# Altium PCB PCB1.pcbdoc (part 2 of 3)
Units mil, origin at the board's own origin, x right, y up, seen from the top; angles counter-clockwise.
Board outline 1393.7 x 1462.72 mil, 2 copper layers (Top Layer, Bottom Layer), stack 62.206 mil thick; 10 components, 35 nets, 86 pads, 11 vias.

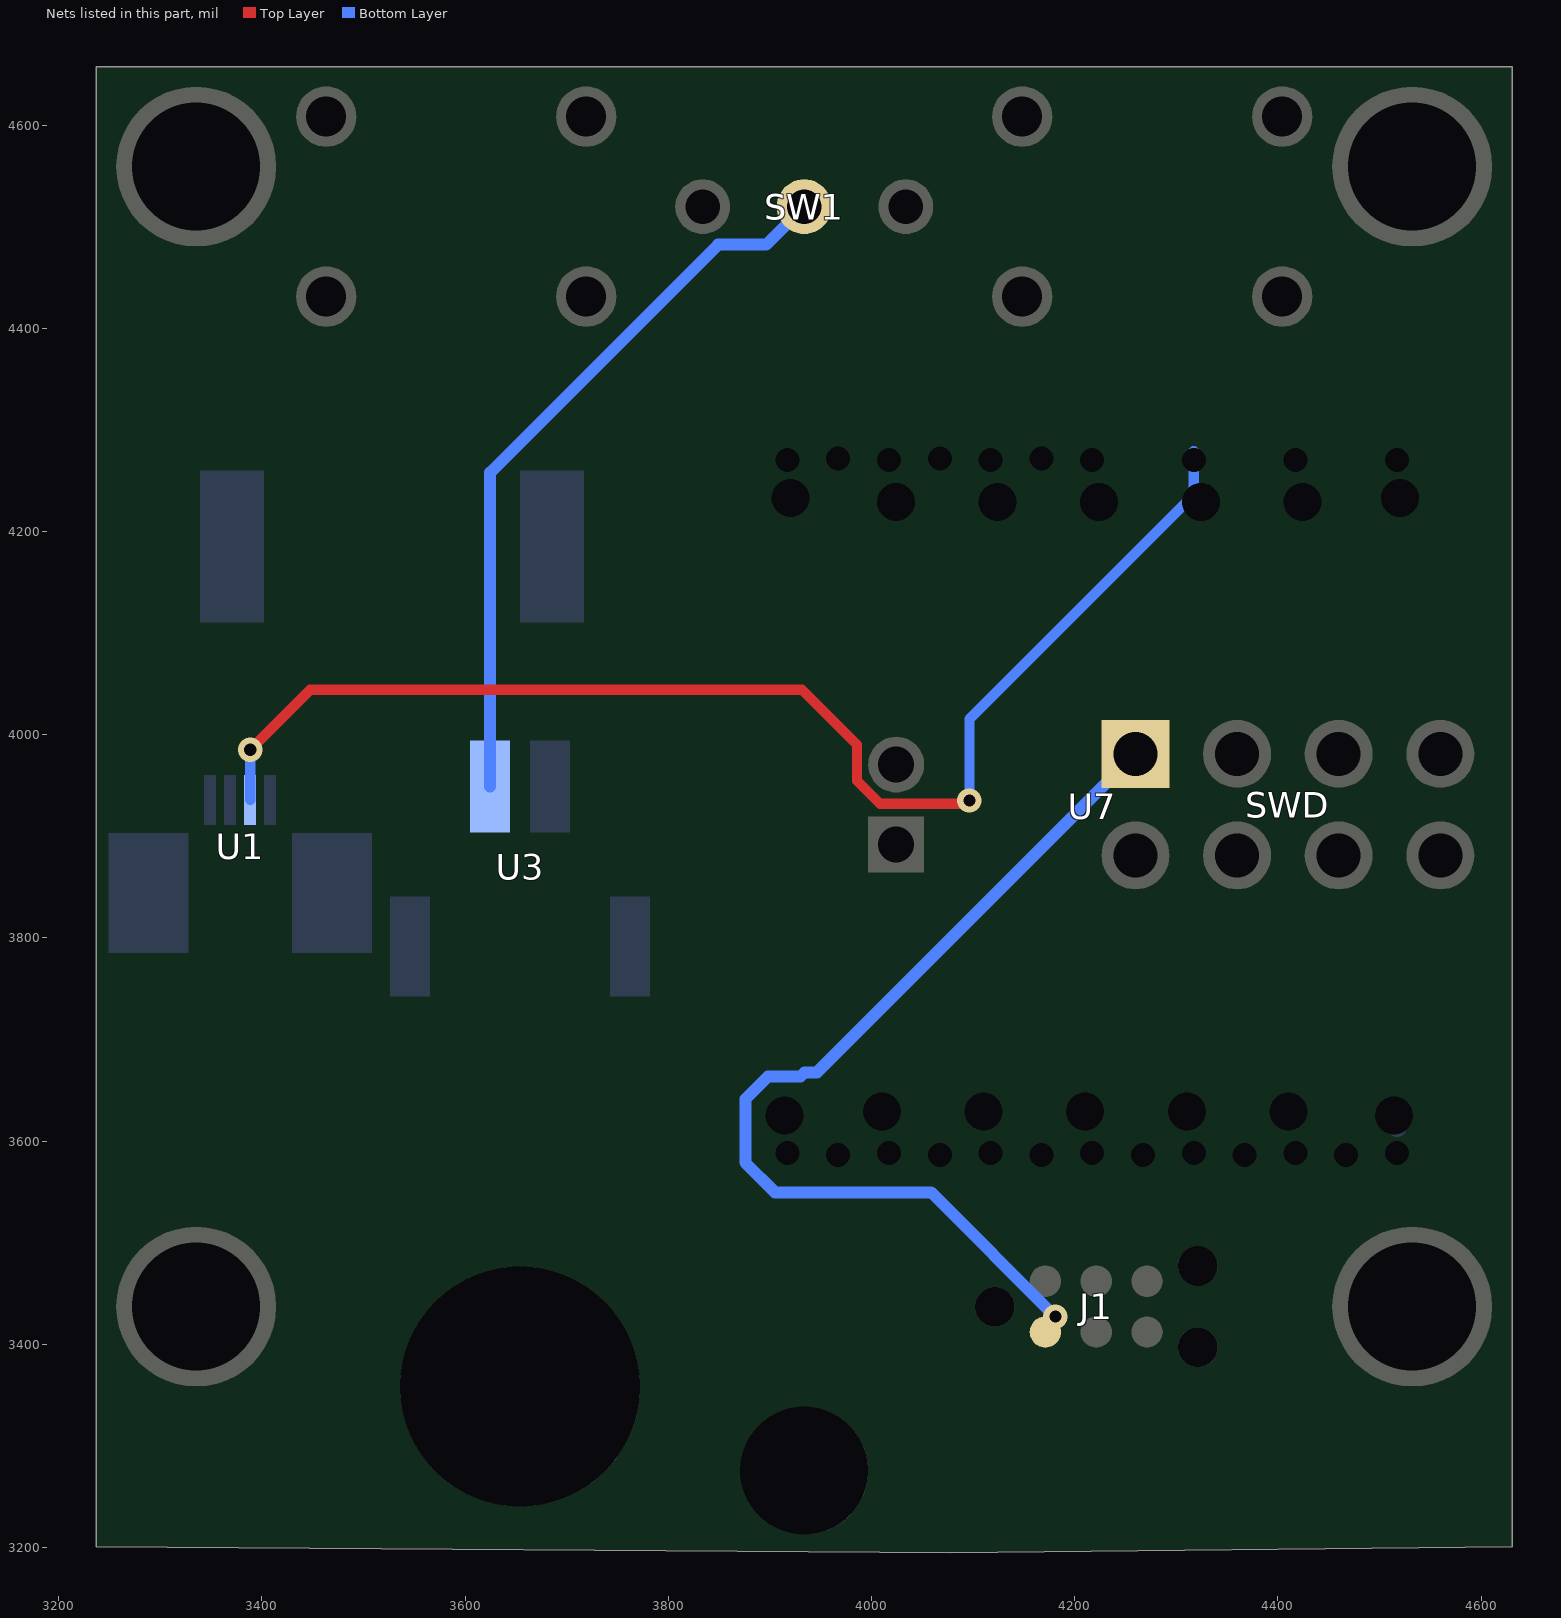
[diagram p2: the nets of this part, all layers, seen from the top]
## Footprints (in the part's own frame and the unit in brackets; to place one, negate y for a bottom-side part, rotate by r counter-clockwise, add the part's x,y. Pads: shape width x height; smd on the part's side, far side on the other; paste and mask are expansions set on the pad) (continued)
Claude_buddy_Seeed_Studio_XIAO_Series:XIAO-Add-On-PRO [mm]
  round 0.673 hole 0.95: 1(7.545,7.72) 2(4.905,7.62) 3(2.365,7.62) 4(-0.175,7.62) 5(-2.715,7.62) 6(-5.255,7.62) 7(-7.695,7.72) 8(-7.545,-7.72) 9(-4.905,-7.62) 10(-2.365,-7.62) 11(0.175,-7.62) 12(2.715,-7.62) 13(5.255,-7.62) 14(7.695,-7.72)
  round 0.475 smd: 1(7.62,8.028)
  round 0.452 hole 0.6: 1(7.62,8.663) 2(5.08,8.663) 3(2.54,8.663) 4(0,8.663) 5(-2.54,8.663) 6(-5.08,8.663) 7(-7.62,8.663) 8(-7.62,-8.663) 9(-5.08,-8.663) 10(-2.54,-8.663) 11(0,-8.663) 12(2.54,-8.663) 13(5.08,-8.663) 14(7.62,-8.663)
  round 0.451 hole 0.6: 15(6.351,8.708) 16(3.811,8.708) 17(1.271,8.708) 18(-1.269,8.708) 19(-3.809,8.708) 20(-6.349,8.708) 21(-6.351,-8.708) 22(-3.811,-8.708) 23(-1.271,-8.708)
  Top Layer region: 7.173,8.941 7.193,9.032 7.232,9.117 7.287,9.193 7.357,9.255 7.438,9.302 7.527,9.33 7.62,9.34 7.713,9.33 7.802,9.302 7.883,9.255 7.953,9.193 8.008,9.117 8.047,9.032 8.067,8.941 8.072,8.941 8.072,8.077 7.168,8.077 7.168,8.941 7.173,8.941
  Top Layer region: 7.145,8.881 7.154,8.891 8.086,8.891 8.095,8.881 8.095,7.166 7.145,7.166
  Top Layer region: 7.545,7.045 7.439,7.053 7.336,7.078 7.239,7.119 7.148,7.174 7.068,7.243 6.999,7.323 6.944,7.414 6.903,7.511 6.878,7.614 6.87,7.72 6.878,7.826 6.903,7.929 6.944,8.026 6.999,8.117 7.068,8.197 7.148,8.266 7.239,8.321 7.336,8.362 7.439,8.387 7.545,8.395 7.651,8.387 7.754,8.362 7.851,8.321 7.942,8.266 8.022,8.197 8.091,8.117 8.146,8.026 8.187,7.929 8.212,7.826 8.22,7.72 8.212,7.614 8.187,7.511 8.146,7.414 8.091,7.323 8.022,7.243 7.942,7.174 7.851,7.119 7.754,7.078 7.651,7.053 7.545,7.045
  Top Layer region: 4.633,8.941 4.653,9.032 4.692,9.117 4.747,9.193 4.817,9.255 4.898,9.302 4.987,9.33 5.08,9.34 5.173,9.33 5.262,9.302 5.343,9.255 5.413,9.193 5.468,9.117 5.507,9.032 5.527,8.941 5.532,8.941 5.532,8.077 4.628,8.077 4.628,8.941 4.633,8.941
  Top Layer region: 4.905,6.945 4.799,6.953 4.696,6.978 4.599,7.019 4.508,7.074 4.428,7.143 4.359,7.223 4.304,7.314 4.263,7.411 4.238,7.514 4.23,7.62 4.238,7.726 4.263,7.829 4.304,7.926 4.359,8.017 4.428,8.097 4.508,8.166 4.599,8.221 4.696,8.262 4.799,8.287 4.905,8.295 5.011,8.287 5.114,8.262 5.211,8.221 5.302,8.166 5.382,8.097 5.451,8.017 5.506,7.926 5.547,7.829 5.572,7.726 5.58,7.62 5.572,7.514 5.547,7.411 5.506,7.314 5.451,7.223 5.382,7.143 5.302,7.074 5.211,7.019 5.114,6.978 5.011,6.953 4.905,6.945
  Top Layer region: 2.093,8.941 2.113,9.032 2.152,9.117 2.207,9.193 2.277,9.255 2.358,9.302 2.447,9.33 2.54,9.34 2.633,9.33 2.722,9.302 2.803,9.255 2.873,9.193 2.928,9.117 2.967,9.032 2.987,8.941 2.992,8.941 2.992,8.077 2.088,8.077 2.088,8.941 2.093,8.941
  Top Layer region: 2.365,6.945 2.259,6.953 2.156,6.978 2.059,7.019 1.968,7.074 1.888,7.143 1.819,7.223 1.764,7.314 1.723,7.411 1.698,7.514 1.69,7.62 1.698,7.726 1.723,7.829 1.764,7.926 1.819,8.017 1.888,8.097 1.968,8.166 2.059,8.221 2.156,8.262 2.259,8.287 2.365,8.295 2.471,8.287 2.574,8.262 2.671,8.221 2.762,8.166 2.842,8.097 2.911,8.017 2.966,7.926 3.007,7.829 3.032,7.726 3.04,7.62 3.032,7.514 3.007,7.411 2.966,7.314 2.911,7.223 2.842,7.143 2.762,7.074 2.671,7.019 2.574,6.978 2.471,6.953 2.365,6.945
  Top Layer region: -0.447,8.941 -0.427,9.032 -0.388,9.117 -0.333,9.193 -0.263,9.255 -0.182,9.302 -0.093,9.33 0,9.34 0.093,9.33 0.182,9.302 0.263,9.255 0.333,9.193 0.388,9.117 0.427,9.032 0.447,8.941 0.452,8.941 0.452,8.077 -0.452,8.077 -0.452,8.941 -0.447,8.941
  Top Layer region: -0.175,6.945 -0.281,6.953 -0.384,6.978 -0.481,7.019 -0.572,7.074 -0.652,7.143 -0.721,7.223 -0.776,7.314 -0.817,7.411 -0.842,7.514 -0.85,7.62 -0.842,7.726 -0.817,7.829 -0.776,7.926 -0.721,8.017 -0.652,8.097 -0.572,8.166 -0.481,8.221 -0.384,8.262 -0.281,8.287 -0.175,8.295 -0.069,8.287 0.034,8.262 0.131,8.221 0.222,8.166 0.302,8.097 0.371,8.017 0.426,7.926 0.467,7.829 0.492,7.726 0.5,7.62 0.492,7.514 0.467,7.411 0.426,7.314 0.371,7.223 0.302,7.143 0.222,7.074 0.131,7.019 0.034,6.978 -0.069,6.953 -0.175,6.945
  Top Layer region: -2.987,8.941 -2.967,9.032 -2.928,9.117 -2.873,9.193 -2.803,9.255 -2.722,9.302 -2.633,9.33 -2.54,9.34 -2.447,9.33 -2.358,9.302 -2.277,9.255 -2.207,9.193 -2.152,9.117 -2.113,9.032 -2.093,8.941 -2.088,8.941 -2.088,8.077 -2.992,8.077 -2.992,8.941 -2.987,8.941
  Top Layer region: -2.715,6.945 -2.821,6.953 -2.924,6.978 -3.021,7.019 -3.112,7.074 -3.192,7.143 -3.261,7.223 -3.316,7.314 -3.357,7.411 -3.382,7.514 -3.39,7.62 -3.382,7.726 -3.357,7.829 -3.316,7.926 -3.261,8.017 -3.192,8.097 -3.112,8.166 -3.021,8.221 -2.924,8.262 -2.821,8.287 -2.715,8.295 -2.609,8.287 -2.506,8.262 -2.409,8.221 -2.318,8.166 -2.238,8.097 -2.169,8.017 -2.114,7.926 -2.073,7.829 -2.048,7.726 -2.04,7.62 -2.048,7.514 -2.073,7.411 -2.114,7.314 -2.169,7.223 -2.238,7.143 -2.318,7.074 -2.409,7.019 -2.506,6.978 -2.609,6.953 -2.715,6.945
  Top Layer region: -5.527,8.941 -5.507,9.032 -5.468,9.117 -5.413,9.193 -5.343,9.255 -5.262,9.302 -5.173,9.33 -5.08,9.34 -4.987,9.33 -4.898,9.302 -4.817,9.255 -4.747,9.193 -4.692,9.117 -4.653,9.032 -4.633,8.941 -4.628,8.941 -4.628,8.077 -5.532,8.077 -5.532,8.941 -5.527,8.941
  Top Layer region: -5.255,6.945 -5.361,6.953 -5.464,6.978 -5.561,7.019 -5.652,7.074 -5.732,7.143 -5.801,7.223 -5.856,7.314 -5.897,7.411 -5.922,7.514 -5.93,7.62 -5.922,7.726 -5.897,7.829 -5.856,7.926 -5.801,8.017 -5.732,8.097 -5.652,8.166 -5.561,8.221 -5.464,8.262 -5.361,8.287 -5.255,8.295 -5.149,8.287 -5.046,8.262 -4.949,8.221 -4.858,8.166 -4.778,8.097 -4.709,8.017 -4.654,7.926 -4.613,7.829 -4.588,7.726 -4.58,7.62 -4.588,7.514 -4.613,7.411 -4.654,7.314 -4.709,7.223 -4.778,7.143 -4.858,7.074 -4.949,7.019 -5.046,6.978 -5.149,6.953 -5.255,6.945
  Top Layer region: -8.067,8.941 -8.047,9.032 -8.008,9.117 -7.953,9.193 -7.883,9.255 -7.802,9.302 -7.713,9.33 -7.62,9.34 -7.527,9.33 -7.438,9.302 -7.357,9.255 -7.287,9.193 -7.232,9.117 -7.193,9.032 -7.173,8.941 -7.168,8.941 -7.168,8.077 -8.072,8.077 -8.072,8.941 -8.067,8.941
  Top Layer region: -7.695,7.045 -7.801,7.053 -7.904,7.078 -8.001,7.119 -8.092,7.174 -8.172,7.243 -8.241,7.323 -8.296,7.414 -8.337,7.511 -8.362,7.614 -8.37,7.72 -8.362,7.826 -8.337,7.929 -8.296,8.026 -8.241,8.117 -8.172,8.197 -8.092,8.266 -8.001,8.321 -7.904,8.362 -7.801,8.387 -7.695,8.395 -7.589,8.387 -7.486,8.362 -7.389,8.321 -7.298,8.266 -7.218,8.197 -7.149,8.117 -7.094,8.026 -7.053,7.929 -7.028,7.826 -7.02,7.72 -7.028,7.614 -7.053,7.511 -7.094,7.414 -7.149,7.323 -7.218,7.243 -7.298,7.174 -7.389,7.119 -7.486,7.078 -7.589,7.053 -7.695,7.045
  Top Layer region: -7.545,-8.395 -7.651,-8.387 -7.754,-8.362 -7.851,-8.321 -7.942,-8.266 -8.022,-8.197 -8.091,-8.117 -8.146,-8.026 -8.187,-7.929 -8.212,-7.826 -8.22,-7.72 -8.212,-7.614 -8.187,-7.511 -8.146,-7.414 -8.091,-7.323 -8.022,-7.243 -7.942,-7.174 -7.851,-7.119 -7.754,-7.078 -7.651,-7.053 -7.545,-7.045 -7.439,-7.053 -7.336,-7.078 -7.239,-7.119 -7.148,-7.174 -7.068,-7.243 -6.999,-7.323 -6.944,-7.414 -6.903,-7.511 -6.878,-7.614 -6.87,-7.72 -6.878,-7.826 -6.903,-7.929 -6.944,-8.026 -6.999,-8.117 -7.068,-8.197 -7.148,-8.266 -7.239,-8.321 -7.336,-8.362 -7.439,-8.387 -7.545,-8.395
  Top Layer region: -7.173,-8.941 -7.193,-9.032 -7.232,-9.117 -7.287,-9.193 -7.357,-9.255 -7.438,-9.302 -7.527,-9.33 -7.62,-9.34 -7.713,-9.33 -7.802,-9.302 -7.883,-9.255 -7.953,-9.193 -8.008,-9.117 -8.047,-9.032 -8.067,-8.941 -8.072,-8.941 -8.072,-8.077 -7.168,-8.077 -7.168,-8.941 -7.173,-8.941
  Top Layer region: -4.905,-8.295 -5.011,-8.287 -5.114,-8.262 -5.211,-8.221 -5.302,-8.166 -5.382,-8.097 -5.451,-8.017 -5.506,-7.926 -5.547,-7.829 -5.572,-7.726 -5.58,-7.62 -5.572,-7.514 -5.547,-7.411 -5.506,-7.314 -5.451,-7.223 -5.382,-7.143 -5.302,-7.074 -5.211,-7.019 -5.114,-6.978 -5.011,-6.953 -4.905,-6.945 -4.799,-6.953 -4.696,-6.978 -4.599,-7.019 -4.508,-7.074 -4.428,-7.143 -4.359,-7.223 -4.304,-7.314 -4.263,-7.411 -4.238,-7.514 -4.23,-7.62 -4.238,-7.726 -4.263,-7.829 -4.304,-7.926 -4.359,-8.017 -4.428,-8.097 -4.508,-8.166 -4.599,-8.221 -4.696,-8.262 -4.799,-8.287 -4.905,-8.295
  Top Layer region: -4.633,-8.941 -4.653,-9.032 -4.692,-9.117 -4.747,-9.193 -4.817,-9.255 -4.898,-9.302 -4.987,-9.33 -5.08,-9.34 -5.173,-9.33 -5.262,-9.302 -5.343,-9.255 -5.413,-9.193 -5.468,-9.117 -5.507,-9.032 -5.527,-8.941 -5.532,-8.941 -5.532,-8.077 -4.628,-8.077 -4.628,-8.941 -4.633,-8.941
  Top Layer region: -2.365,-8.295 -2.471,-8.287 -2.574,-8.262 -2.671,-8.221 -2.762,-8.166 -2.842,-8.097 -2.911,-8.017 -2.966,-7.926 -3.007,-7.829 -3.032,-7.726 -3.04,-7.62 -3.032,-7.514 -3.007,-7.411 -2.966,-7.314 -2.911,-7.223 -2.842,-7.143 -2.762,-7.074 -2.671,-7.019 -2.574,-6.978 -2.471,-6.953 -2.365,-6.945 -2.259,-6.953 -2.156,-6.978 -2.059,-7.019 -1.968,-7.074 -1.888,-7.143 -1.819,-7.223 -1.764,-7.314 -1.723,-7.411 -1.698,-7.514 -1.69,-7.62 -1.698,-7.726 -1.723,-7.829 -1.764,-7.926 -1.819,-8.017 -1.888,-8.097 -1.968,-8.166 -2.059,-8.221 -2.156,-8.262 -2.259,-8.287 -2.365,-8.295
  Top Layer region: -2.093,-8.941 -2.113,-9.032 -2.152,-9.117 -2.207,-9.193 -2.277,-9.255 -2.358,-9.302 -2.447,-9.33 -2.54,-9.34 -2.633,-9.33 -2.722,-9.302 -2.803,-9.255 -2.873,-9.193 -2.928,-9.117 -2.967,-9.032 -2.987,-8.941 -2.992,-8.941 -2.992,-8.077 -2.088,-8.077 -2.088,-8.941 -2.093,-8.941
  Top Layer region: 0.175,-8.295 0.069,-8.287 -0.034,-8.262 -0.131,-8.221 -0.222,-8.166 -0.302,-8.097 -0.371,-8.017 -0.426,-7.926 -0.467,-7.829 -0.492,-7.726 -0.5,-7.62 -0.492,-7.514 -0.467,-7.411 -0.426,-7.314 -0.371,-7.223 -0.302,-7.143 -0.222,-7.074 -0.131,-7.019 -0.034,-6.978 0.069,-6.953 0.175,-6.945 0.281,-6.953 0.384,-6.978 0.481,-7.019 0.572,-7.074 0.652,-7.143 0.721,-7.223 0.776,-7.314 0.817,-7.411 0.842,-7.514 0.85,-7.62 0.842,-7.726 0.817,-7.829 0.776,-7.926 0.721,-8.017 0.652,-8.097 0.572,-8.166 0.481,-8.221 0.384,-8.262 0.281,-8.287 0.175,-8.295
  Top Layer region: 0.447,-8.941 0.427,-9.032 0.388,-9.117 0.333,-9.193 0.263,-9.255 0.182,-9.302 0.093,-9.33 0,-9.34 -0.093,-9.33 -0.182,-9.302 -0.263,-9.255 -0.333,-9.193 -0.388,-9.117 -0.427,-9.032 -0.447,-8.941 -0.452,-8.941 -0.452,-8.077 0.452,-8.077 0.452,-8.941 0.447,-8.941
  Top Layer region: 2.715,-8.295 2.609,-8.287 2.506,-8.262 2.409,-8.221 2.318,-8.166 2.238,-8.097 2.169,-8.017 2.114,-7.926 2.073,-7.829 2.048,-7.726 2.04,-7.62 2.048,-7.514 2.073,-7.411 2.114,-7.314 2.169,-7.223 2.238,-7.143 2.318,-7.074 2.409,-7.019 2.506,-6.978 2.609,-6.953 2.715,-6.945 2.821,-6.953 2.924,-6.978 3.021,-7.019 3.112,-7.074 3.192,-7.143 3.261,-7.223 3.316,-7.314 3.357,-7.411 3.382,-7.514 3.39,-7.62 3.382,-7.726 3.357,-7.829 3.316,-7.926 3.261,-8.017 3.192,-8.097 3.112,-8.166 3.021,-8.221 2.924,-8.262 2.821,-8.287 2.715,-8.295
  Top Layer region: 2.987,-8.941 2.967,-9.032 2.928,-9.117 2.873,-9.193 2.803,-9.255 2.722,-9.302 2.633,-9.33 2.54,-9.34 2.447,-9.33 2.358,-9.302 2.277,-9.255 2.207,-9.193 2.152,-9.117 2.113,-9.032 2.093,-8.941 2.088,-8.941 2.088,-8.077 2.992,-8.077 2.992,-8.941 2.987,-8.941
  Top Layer region: 5.255,-8.295 5.149,-8.287 5.046,-8.262 4.949,-8.221 4.858,-8.166 4.778,-8.097 4.709,-8.017 4.654,-7.926 4.613,-7.829 4.588,-7.726 4.58,-7.62 4.588,-7.514 4.613,-7.411 4.654,-7.314 4.709,-7.223 4.778,-7.143 4.858,-7.074 4.949,-7.019 5.046,-6.978 5.149,-6.953 5.255,-6.945 5.361,-6.953 5.464,-6.978 5.561,-7.019 5.652,-7.074 5.732,-7.143 5.801,-7.223 5.856,-7.314 5.897,-7.411 5.922,-7.514 5.93,-7.62 5.922,-7.726 5.897,-7.829 5.856,-7.926 5.801,-8.017 5.732,-8.097 5.652,-8.166 5.561,-8.221 5.464,-8.262 5.361,-8.287 5.255,-8.295
  Top Layer region: 5.527,-8.941 5.507,-9.032 5.468,-9.117 5.413,-9.193 5.343,-9.255 5.262,-9.302 5.173,-9.33 5.08,-9.34 4.987,-9.33 4.898,-9.302 4.817,-9.255 4.747,-9.193 4.692,-9.117 4.653,-9.032 4.633,-8.941 4.628,-8.941 4.628,-8.077 5.532,-8.077 5.532,-8.941 5.527,-8.941
  Top Layer region: 7.695,-8.395 7.589,-8.387 7.486,-8.362 7.389,-8.321 7.298,-8.266 7.218,-8.197 7.149,-8.117 7.094,-8.026 7.053,-7.929 7.028,-7.826 7.02,-7.72 7.028,-7.614 7.053,-7.511 7.094,-7.414 7.149,-7.323 7.218,-7.243 7.298,-7.174 7.389,-7.119 7.486,-7.078 7.589,-7.053 7.695,-7.045 7.801,-7.053 7.904,-7.078 8.001,-7.119 8.092,-7.174 8.172,-7.243 8.241,-7.323 8.296,-7.414 8.337,-7.511 8.362,-7.614 8.37,-7.72 8.362,-7.826 8.337,-7.929 8.296,-8.026 8.241,-8.117 8.172,-8.197 8.092,-8.266 8.001,-8.321 7.904,-8.362 7.801,-8.387 7.695,-8.395
  Top Layer region: 8.067,-8.941 8.047,-9.032 8.008,-9.117 7.953,-9.193 7.883,-9.255 7.802,-9.302 7.713,-9.33 7.62,-9.34 7.527,-9.33 7.438,-9.302 7.357,-9.255 7.287,-9.193 7.232,-9.117 7.193,-9.032 7.173,-8.941 7.168,-8.941 7.168,-8.077 8.072,-8.077 8.072,-8.941 8.067,-8.941
  Top Layer region: 6.35,9.34 6.443,9.33 6.532,9.302 6.613,9.255 6.683,9.193 6.738,9.117 6.777,9.032 6.797,8.941 6.802,8.941 6.802,8.505 6.781,8.375 6.72,8.255 6.621,8.156 6.378,8.077 6.326,8.077 6.196,8.098 6.076,8.159 5.977,8.258 5.898,8.501 5.898,8.941 5.903,8.941 5.923,9.032 5.962,9.117 6.017,9.193 6.087,9.255 6.168,9.302 6.257,9.33 6.35,9.34
  Top Layer region: 3.81,9.34 3.903,9.33 3.992,9.302 4.073,9.255 4.143,9.193 4.198,9.117 4.237,9.032 4.257,8.941 4.262,8.941 4.262,8.505 4.241,8.375 4.18,8.255 4.081,8.156 3.838,8.077 3.786,8.077 3.656,8.098 3.536,8.159 3.437,8.258 3.358,8.501 3.358,8.941 3.363,8.941 3.383,9.032 3.422,9.117 3.477,9.193 3.547,9.255 3.628,9.302 3.717,9.33 3.81,9.34
  Top Layer region: 1.27,9.34 1.363,9.33 1.452,9.302 1.533,9.255 1.603,9.193 1.658,9.117 1.697,9.032 1.717,8.941 1.722,8.941 1.722,8.505 1.701,8.375 1.64,8.255 1.541,8.156 1.298,8.077 1.246,8.077 1.116,8.098 0.996,8.159 0.897,8.258 0.818,8.501 0.818,8.941 0.823,8.941 0.843,9.032 0.882,9.117 0.937,9.193 1.007,9.255 1.088,9.302 1.177,9.33 1.27,9.34
  Top Layer region: -1.27,9.34 -1.177,9.33 -1.088,9.302 -1.007,9.255 -0.937,9.193 -0.882,9.117 -0.843,9.032 -0.823,8.941 -0.818,8.941 -0.818,8.505 -0.839,8.375 -0.9,8.255 -0.999,8.156 -1.242,8.077 -1.294,8.077 -1.424,8.098 -1.544,8.159 -1.643,8.258 -1.722,8.501 -1.722,8.941 -1.717,8.941 -1.697,9.032 -1.658,9.117 -1.603,9.193 -1.533,9.255 -1.452,9.302 -1.363,9.33 -1.27,9.34
  Top Layer region: -3.81,9.34 -3.717,9.33 -3.628,9.302 -3.547,9.255 -3.477,9.193 -3.422,9.117 -3.383,9.032 -3.363,8.941 -3.358,8.941 -3.358,8.505 -3.379,8.375 -3.44,8.255 -3.539,8.156 -3.782,8.077 -3.834,8.077 -3.964,8.098 -4.084,8.159 -4.183,8.258 -4.262,8.501 -4.262,8.941 -4.257,8.941 -4.237,9.032 -4.198,9.117 -4.143,9.193 -4.073,9.255 -3.992,9.302 -3.903,9.33 -3.81,9.34
  Top Layer region: -6.35,9.34 -6.257,9.33 -6.168,9.302 -6.087,9.255 -6.017,9.193 -5.962,9.117 -5.923,9.032 -5.903,8.941 -5.898,8.941 -5.898,8.505 -5.919,8.375 -5.98,8.255 -6.079,8.156 -6.322,8.077 -6.374,8.077 -6.504,8.098 -6.624,8.159 -6.723,8.258 -6.802,8.501 -6.802,8.941 -6.797,8.941 -6.777,9.032 -6.738,9.117 -6.683,9.193 -6.613,9.255 -6.532,9.302 -6.443,9.33 -6.35,9.34
  Top Layer region: -6.35,-9.34 -6.443,-9.33 -6.532,-9.302 -6.613,-9.255 -6.683,-9.193 -6.738,-9.117 -6.777,-9.032 -6.797,-8.941 -6.802,-8.941 -6.802,-8.505 -6.781,-8.375 -6.72,-8.255 -6.621,-8.156 -6.378,-8.077 -6.326,-8.077 -6.196,-8.098 -6.076,-8.159 -5.977,-8.258 -5.898,-8.501 -5.898,-8.941 -5.903,-8.941 -5.923,-9.032 -5.962,-9.117 -6.017,-9.193 -6.087,-9.255 -6.168,-9.302 -6.257,-9.33 -6.35,-9.34
  Top Layer region: -3.81,-9.34 -3.903,-9.33 -3.992,-9.302 -4.073,-9.255 -4.143,-9.193 -4.198,-9.117 -4.237,-9.032 -4.257,-8.941 -4.262,-8.941 -4.262,-8.505 -4.241,-8.375 -4.18,-8.255 -4.081,-8.156 -3.838,-8.077 -3.786,-8.077 -3.656,-8.098 -3.536,-8.159 -3.437,-8.258 -3.358,-8.501 -3.358,-8.941 -3.363,-8.941 -3.383,-9.032 -3.422,-9.117 -3.477,-9.193 -3.547,-9.255 -3.628,-9.302 -3.717,-9.33 -3.81,-9.34
  Top Layer region: -1.27,-9.34 -1.363,-9.33 -1.452,-9.302 -1.533,-9.255 -1.603,-9.193 -1.658,-9.117 -1.697,-9.032 -1.717,-8.941 -1.722,-8.941 -1.722,-8.505 -1.701,-8.375 -1.64,-8.255 -1.541,-8.156 -1.298,-8.077 -1.246,-8.077 -1.116,-8.098 -0.996,-8.159 -0.897,-8.258 -0.818,-8.501 -0.818,-8.941 -0.823,-8.941 -0.843,-9.032 -0.882,-9.117 -0.937,-9.193 -1.007,-9.255 -1.088,-9.302 -1.177,-9.33 -1.27,-9.34
  Bottom Layer region: 7.173,8.941 7.193,9.032 7.232,9.117 7.287,9.193 7.357,9.255 7.438,9.302 7.527,9.33 7.62,9.34 7.713,9.33 7.802,9.302 7.883,9.255 7.953,9.193 8.008,9.117 8.047,9.032 8.067,8.941 8.072,8.941 8.072,8.077 7.168,8.077 7.168,8.941 7.173,8.941
  Bottom Layer region: 7.545,7.045 7.439,7.053 7.336,7.078 7.239,7.119 7.148,7.174 7.068,7.243 6.999,7.323 6.944,7.414 6.903,7.511 6.878,7.614 6.87,7.72 6.878,7.826 6.903,7.929 6.944,8.026 6.999,8.117 7.068,8.197 7.148,8.266 7.239,8.321 7.336,8.362 7.439,8.387 7.545,8.395 7.651,8.387 7.754,8.362 7.851,8.321 7.942,8.266 8.022,8.197 8.091,8.117 8.146,8.026 8.187,7.929 8.212,7.826 8.22,7.72 8.212,7.614 8.187,7.511 8.146,7.414 8.091,7.323 8.022,7.243 7.942,7.174 7.851,7.119 7.754,7.078 7.651,7.053 7.545,7.045
  Bottom Layer region: 4.633,8.941 4.653,9.032 4.692,9.117 4.747,9.193 4.817,9.255 4.898,9.302 4.987,9.33 5.08,9.34 5.173,9.33 5.262,9.302 5.343,9.255 5.413,9.193 5.468,9.117 5.507,9.032 5.527,8.941 5.532,8.941 5.532,8.077 4.628,8.077 4.628,8.941 4.633,8.941
  Bottom Layer region: 4.905,6.945 4.799,6.953 4.696,6.978 4.599,7.019 4.508,7.074 4.428,7.143 4.359,7.223 4.304,7.314 4.263,7.411 4.238,7.514 4.23,7.62 4.238,7.726 4.263,7.829 4.304,7.926 4.359,8.017 4.428,8.097 4.508,8.166 4.599,8.221 4.696,8.262 4.799,8.287 4.905,8.295 5.011,8.287 5.114,8.262 5.211,8.221 5.302,8.166 5.382,8.097 5.451,8.017 5.506,7.926 5.547,7.829 5.572,7.726 5.58,7.62 5.572,7.514 5.547,7.411 5.506,7.314 5.451,7.223 5.382,7.143 5.302,7.074 5.211,7.019 5.114,6.978 5.011,6.953 4.905,6.945
  Bottom Layer region: 2.093,8.941 2.113,9.032 2.152,9.117 2.207,9.193 2.277,9.255 2.358,9.302 2.447,9.33 2.54,9.34 2.633,9.33 2.722,9.302 2.803,9.255 2.873,9.193 2.928,9.117 2.967,9.032 2.987,8.941 2.992,8.941 2.992,8.077 2.088,8.077 2.088,8.941 2.093,8.941
  Bottom Layer region: 2.365,6.945 2.259,6.953 2.156,6.978 2.059,7.019 1.968,7.074 1.888,7.143 1.819,7.223 1.764,7.314 1.723,7.411 1.698,7.514 1.69,7.62 1.698,7.726 1.723,7.829 1.764,7.926 1.819,8.017 1.888,8.097 1.968,8.166 2.059,8.221 2.156,8.262 2.259,8.287 2.365,8.295 2.471,8.287 2.574,8.262 2.671,8.221 2.762,8.166 2.842,8.097 2.911,8.017 2.966,7.926 3.007,7.829 3.032,7.726 3.04,7.62 3.032,7.514 3.007,7.411 2.966,7.314 2.911,7.223 2.842,7.143 2.762,7.074 2.671,7.019 2.574,6.978 2.471,6.953 2.365,6.945
  Bottom Layer region: -0.447,8.941 -0.427,9.032 -0.388,9.117 -0.333,9.193 -0.263,9.255 -0.182,9.302 -0.093,9.33 0,9.34 0.093,9.33 0.182,9.302 0.263,9.255 0.333,9.193 0.388,9.117 0.427,9.032 0.447,8.941 0.452,8.941 0.452,8.077 -0.452,8.077 -0.452,8.941 -0.447,8.941
  Bottom Layer region: -0.175,6.945 -0.281,6.953 -0.384,6.978 -0.481,7.019 -0.572,7.074 -0.652,7.143 -0.721,7.223 -0.776,7.314 -0.817,7.411 -0.842,7.514 -0.85,7.62 -0.842,7.726 -0.817,7.829 -0.776,7.926 -0.721,8.017 -0.652,8.097 -0.572,8.166 -0.481,8.221 -0.384,8.262 -0.281,8.287 -0.175,8.295 -0.069,8.287 0.034,8.262 0.131,8.221 0.222,8.166 0.302,8.097 0.371,8.017 0.426,7.926 0.467,7.829 0.492,7.726 0.5,7.62 0.492,7.514 0.467,7.411 0.426,7.314 0.371,7.223 0.302,7.143 0.222,7.074 0.131,7.019 0.034,6.978 -0.069,6.953 -0.175,6.945
  Bottom Layer region: -2.987,8.941 -2.967,9.032 -2.928,9.117 -2.873,9.193 -2.803,9.255 -2.722,9.302 -2.633,9.33 -2.54,9.34 -2.447,9.33 -2.358,9.302 -2.277,9.255 -2.207,9.193 -2.152,9.117 -2.113,9.032 -2.093,8.941 -2.088,8.941 -2.088,8.077 -2.992,8.077 -2.992,8.941 -2.987,8.941
  Bottom Layer region: -2.715,6.945 -2.821,6.953 -2.924,6.978 -3.021,7.019 -3.112,7.074 -3.192,7.143 -3.261,7.223 -3.316,7.314 -3.357,7.411 -3.382,7.514 -3.39,7.62 -3.382,7.726 -3.357,7.829 -3.316,7.926 -3.261,8.017 -3.192,8.097 -3.112,8.166 -3.021,8.221 -2.924,8.262 -2.821,8.287 -2.715,8.295 -2.609,8.287 -2.506,8.262 -2.409,8.221 -2.318,8.166 -2.238,8.097 -2.169,8.017 -2.114,7.926 -2.073,7.829 -2.048,7.726 -2.04,7.62 -2.048,7.514 -2.073,7.411 -2.114,7.314 -2.169,7.223 -2.238,7.143 -2.318,7.074 -2.409,7.019 -2.506,6.978 -2.609,6.953 -2.715,6.945
  Bottom Layer region: -5.527,8.941 -5.507,9.032 -5.468,9.117 -5.413,9.193 -5.343,9.255 -5.262,9.302 -5.173,9.33 -5.08,9.34 -4.987,9.33 -4.898,9.302 -4.817,9.255 -4.747,9.193 -4.692,9.117 -4.653,9.032 -4.633,8.941 -4.628,8.941 -4.628,8.077 -5.532,8.077 -5.532,8.941 -5.527,8.941
  Bottom Layer region: -5.255,6.945 -5.361,6.953 -5.464,6.978 -5.561,7.019 -5.652,7.074 -5.732,7.143 -5.801,7.223 -5.856,7.314 -5.897,7.411 -5.922,7.514 -5.93,7.62 -5.922,7.726 -5.897,7.829 -5.856,7.926 -5.801,8.017 -5.732,8.097 -5.652,8.166 -5.561,8.221 -5.464,8.262 -5.361,8.287 -5.255,8.295 -5.149,8.287 -5.046,8.262 -4.949,8.221 -4.858,8.166 -4.778,8.097 -4.709,8.017 -4.654,7.926 -4.613,7.829 -4.588,7.726 -4.58,7.62 -4.588,7.514 -4.613,7.411 -4.654,7.314 -4.709,7.223 -4.778,7.143 -4.858,7.074 -4.949,7.019 -5.046,6.978 -5.149,6.953 -5.255,6.945
  Bottom Layer region: -8.067,8.941 -8.047,9.032 -8.008,9.117 -7.953,9.193 -7.883,9.255 -7.802,9.302 -7.713,9.33 -7.62,9.34 -7.527,9.33 -7.438,9.302 -7.357,9.255 -7.287,9.193 -7.232,9.117 -7.193,9.032 -7.173,8.941 -7.168,8.941 -7.168,8.077 -8.072,8.077 -8.072,8.941 -8.067,8.941
  Bottom Layer region: -7.695,7.045 -7.801,7.053 -7.904,7.078 -8.001,7.119 -8.092,7.174 -8.172,7.243 -8.241,7.323 -8.296,7.414 -8.337,7.511 -8.362,7.614 -8.37,7.72 -8.362,7.826 -8.337,7.929 -8.296,8.026 -8.241,8.117 -8.172,8.197 -8.092,8.266 -8.001,8.321 -7.904,8.362 -7.801,8.387 -7.695,8.395 -7.589,8.387 -7.486,8.362 -7.389,8.321 -7.298,8.266 -7.218,8.197 -7.149,8.117 -7.094,8.026 -7.053,7.929 -7.028,7.826 -7.02,7.72 -7.028,7.614 -7.053,7.511 -7.094,7.414 -7.149,7.323 -7.218,7.243 -7.298,7.174 -7.389,7.119 -7.486,7.078 -7.589,7.053 -7.695,7.045
  Bottom Layer region: -7.545,-8.395 -7.651,-8.387 -7.754,-8.362 -7.851,-8.321 -7.942,-8.266 -8.022,-8.197 -8.091,-8.117 -8.146,-8.026 -8.187,-7.929 -8.212,-7.826 -8.22,-7.72 -8.212,-7.614 -8.187,-7.511 -8.146,-7.414 -8.091,-7.323 -8.022,-7.243 -7.942,-7.174 -7.851,-7.119 -7.754,-7.078 -7.651,-7.053 -7.545,-7.045 -7.439,-7.053 -7.336,-7.078 -7.239,-7.119 -7.148,-7.174 -7.068,-7.243 -6.999,-7.323 -6.944,-7.414 -6.903,-7.511 -6.878,-7.614 -6.87,-7.72 -6.878,-7.826 -6.903,-7.929 -6.944,-8.026 -6.999,-8.117 -7.068,-8.197 -7.148,-8.266 -7.239,-8.321 -7.336,-8.362 -7.439,-8.387 -7.545,-8.395
  Bottom Layer region: -7.173,-8.941 -7.193,-9.032 -7.232,-9.117 -7.287,-9.193 -7.357,-9.255 -7.438,-9.302 -7.527,-9.33 -7.62,-9.34 -7.713,-9.33 -7.802,-9.302 -7.883,-9.255 -7.953,-9.193 -8.008,-9.117 -8.047,-9.032 -8.067,-8.941 -8.072,-8.941 -8.072,-8.077 -7.168,-8.077 -7.168,-8.941 -7.173,-8.941
  Bottom Layer region: -4.905,-8.295 -5.011,-8.287 -5.114,-8.262 -5.211,-8.221 -5.302,-8.166 -5.382,-8.097 -5.451,-8.017 -5.506,-7.926 -5.547,-7.829 -5.572,-7.726 -5.58,-7.62 -5.572,-7.514 -5.547,-7.411 -5.506,-7.314 -5.451,-7.223 -5.382,-7.143 -5.302,-7.074 -5.211,-7.019 -5.114,-6.978 -5.011,-6.953 -4.905,-6.945 -4.799,-6.953 -4.696,-6.978 -4.599,-7.019 -4.508,-7.074 -4.428,-7.143 -4.359,-7.223 -4.304,-7.314 -4.263,-7.411 -4.238,-7.514 -4.23,-7.62 -4.238,-7.726 -4.263,-7.829 -4.304,-7.926 -4.359,-8.017 -4.428,-8.097 -4.508,-8.166 -4.599,-8.221 -4.696,-8.262 -4.799,-8.287 -4.905,-8.295
  Bottom Layer region: -4.633,-8.941 -4.653,-9.032 -4.692,-9.117 -4.747,-9.193 -4.817,-9.255 -4.898,-9.302 -4.987,-9.33 -5.08,-9.34 -5.173,-9.33 -5.262,-9.302 -5.343,-9.255 -5.413,-9.193 -5.468,-9.117 -5.507,-9.032 -5.527,-8.941 -5.532,-8.941 -5.532,-8.077 -4.628,-8.077 -4.628,-8.941 -4.633,-8.941
  Bottom Layer region: -2.365,-8.295 -2.471,-8.287 -2.574,-8.262 -2.671,-8.221 -2.762,-8.166 -2.842,-8.097 -2.911,-8.017 -2.966,-7.926 -3.007,-7.829 -3.032,-7.726 -3.04,-7.62 -3.032,-7.514 -3.007,-7.411 -2.966,-7.314 -2.911,-7.223 -2.842,-7.143 -2.762,-7.074 -2.671,-7.019 -2.574,-6.978 -2.471,-6.953 -2.365,-6.945 -2.259,-6.953 -2.156,-6.978 -2.059,-7.019 -1.968,-7.074 -1.888,-7.143 -1.819,-7.223 -1.764,-7.314 -1.723,-7.411 -1.698,-7.514 -1.69,-7.62 -1.698,-7.726 -1.723,-7.829 -1.764,-7.926 -1.819,-8.017 -1.888,-8.097 -1.968,-8.166 -2.059,-8.221 -2.156,-8.262 -2.259,-8.287 -2.365,-8.295
  Bottom Layer region: -2.093,-8.941 -2.113,-9.032 -2.152,-9.117 -2.207,-9.193 -2.277,-9.255 -2.358,-9.302 -2.447,-9.33 -2.54,-9.34 -2.633,-9.33 -2.722,-9.302 -2.803,-9.255 -2.873,-9.193 -2.928,-9.117 -2.967,-9.032 -2.987,-8.941 -2.992,-8.941 -2.992,-8.077 -2.088,-8.077 -2.088,-8.941 -2.093,-8.941
  Bottom Layer region: 0.175,-8.295 0.069,-8.287 -0.034,-8.262 -0.131,-8.221 -0.222,-8.166 -0.302,-8.097 -0.371,-8.017 -0.426,-7.926 -0.467,-7.829 -0.492,-7.726 -0.5,-7.62 -0.492,-7.514 -0.467,-7.411 -0.426,-7.314 -0.371,-7.223 -0.302,-7.143 -0.222,-7.074 -0.131,-7.019 -0.034,-6.978 0.069,-6.953 0.175,-6.945 0.281,-6.953 0.384,-6.978 0.481,-7.019 0.572,-7.074 0.652,-7.143 0.721,-7.223 0.776,-7.314 0.817,-7.411 0.842,-7.514 0.85,-7.62 0.842,-7.726 0.817,-7.829 0.776,-7.926 0.721,-8.017 0.652,-8.097 0.572,-8.166 0.481,-8.221 0.384,-8.262 0.281,-8.287 0.175,-8.295
  Bottom Layer region: 0.447,-8.941 0.427,-9.032 0.388,-9.117 0.333,-9.193 0.263,-9.255 0.182,-9.302 0.093,-9.33 0,-9.34 -0.093,-9.33 -0.182,-9.302 -0.263,-9.255 -0.333,-9.193 -0.388,-9.117 -0.427,-9.032 -0.447,-8.941 -0.452,-8.941 -0.452,-8.077 0.452,-8.077 0.452,-8.941 0.447,-8.941
  Bottom Layer region: 2.715,-8.295 2.609,-8.287 2.506,-8.262 2.409,-8.221 2.318,-8.166 2.238,-8.097 2.169,-8.017 2.114,-7.926 2.073,-7.829 2.048,-7.726 2.04,-7.62 2.048,-7.514 2.073,-7.411 2.114,-7.314 2.169,-7.223 2.238,-7.143 2.318,-7.074 2.409,-7.019 2.506,-6.978 2.609,-6.953 2.715,-6.945 2.821,-6.953 2.924,-6.978 3.021,-7.019 3.112,-7.074 3.192,-7.143 3.261,-7.223 3.316,-7.314 3.357,-7.411 3.382,-7.514 3.39,-7.62 3.382,-7.726 3.357,-7.829 3.316,-7.926 3.261,-8.017 3.192,-8.097 3.112,-8.166 3.021,-8.221 2.924,-8.262 2.821,-8.287 2.715,-8.295
  Bottom Layer region: 2.987,-8.941 2.967,-9.032 2.928,-9.117 2.873,-9.193 2.803,-9.255 2.722,-9.302 2.633,-9.33 2.54,-9.34 2.447,-9.33 2.358,-9.302 2.277,-9.255 2.207,-9.193 2.152,-9.117 2.113,-9.032 2.093,-8.941 2.088,-8.941 2.088,-8.077 2.992,-8.077 2.992,-8.941 2.987,-8.941
  Bottom Layer region: 5.255,-8.295 5.149,-8.287 5.046,-8.262 4.949,-8.221 4.858,-8.166 4.778,-8.097 4.709,-8.017 4.654,-7.926 4.613,-7.829 4.588,-7.726 4.58,-7.62 4.588,-7.514 4.613,-7.411 4.654,-7.314 4.709,-7.223 4.778,-7.143 4.858,-7.074 4.949,-7.019 5.046,-6.978 5.149,-6.953 5.255,-6.945 5.361,-6.953 5.464,-6.978 5.561,-7.019 5.652,-7.074 5.732,-7.143 5.801,-7.223 5.856,-7.314 5.897,-7.411 5.922,-7.514 5.93,-7.62 5.922,-7.726 5.897,-7.829 5.856,-7.926 5.801,-8.017 5.732,-8.097 5.652,-8.166 5.561,-8.221 5.464,-8.262 5.361,-8.287 5.255,-8.295
  Bottom Layer region: 5.527,-8.941 5.507,-9.032 5.468,-9.117 5.413,-9.193 5.343,-9.255 5.262,-9.302 5.173,-9.33 5.08,-9.34 4.987,-9.33 4.898,-9.302 4.817,-9.255 4.747,-9.193 4.692,-9.117 4.653,-9.032 4.633,-8.941 4.628,-8.941 4.628,-8.077 5.532,-8.077 5.532,-8.941 5.527,-8.941
  Bottom Layer region: 7.695,-8.395 7.589,-8.387 7.486,-8.362 7.389,-8.321 7.298,-8.266 7.218,-8.197 7.149,-8.117 7.094,-8.026 7.053,-7.929 7.028,-7.826 7.02,-7.72 7.028,-7.614 7.053,-7.511 7.094,-7.414 7.149,-7.323 7.218,-7.243 7.298,-7.174 7.389,-7.119 7.486,-7.078 7.589,-7.053 7.695,-7.045 7.801,-7.053 7.904,-7.078 8.001,-7.119 8.092,-7.174 8.172,-7.243 8.241,-7.323 8.296,-7.414 8.337,-7.511 8.362,-7.614 8.37,-7.72 8.362,-7.826 8.337,-7.929 8.296,-8.026 8.241,-8.117 8.172,-8.197 8.092,-8.266 8.001,-8.321 7.904,-8.362 7.801,-8.387 7.695,-8.395
  Bottom Layer region: 8.067,-8.941 8.047,-9.032 8.008,-9.117 7.953,-9.193 7.883,-9.255 7.802,-9.302 7.713,-9.33 7.62,-9.34 7.527,-9.33 7.438,-9.302 7.357,-9.255 7.287,-9.193 7.232,-9.117 7.193,-9.032 7.173,-8.941 7.168,-8.941 7.168,-8.077 8.072,-8.077 8.072,-8.941 8.067,-8.941
  Bottom Layer region: 6.35,9.34 6.443,9.33 6.532,9.302 6.613,9.255 6.683,9.193 6.738,9.117 6.777,9.032 6.797,8.941 6.802,8.941 6.802,8.505 6.781,8.375 6.72,8.255 6.621,8.156 6.378,8.077 6.326,8.077 6.196,8.098 6.076,8.159 5.977,8.258 5.898,8.501 5.898,8.941 5.903,8.941 5.923,9.032 5.962,9.117 6.017,9.193 6.087,9.255 6.168,9.302 6.257,9.33 6.35,9.34
  Bottom Layer region: 3.81,9.34 3.903,9.33 3.992,9.302 4.073,9.255 4.143,9.193 4.198,9.117 4.237,9.032 4.257,8.941 4.262,8.941 4.262,8.505 4.241,8.375 4.18,8.255 4.081,8.156 3.838,8.077 3.786,8.077 3.656,8.098 3.536,8.159 3.437,8.258 3.358,8.501 3.358,8.941 3.363,8.941 3.383,9.032 3.422,9.117 3.477,9.193 3.547,9.255 3.628,9.302 3.717,9.33 3.81,9.34
  Bottom Layer region: 1.27,9.34 1.363,9.33 1.452,9.302 1.533,9.255 1.603,9.193 1.658,9.117 1.697,9.032 1.717,8.941 1.722,8.941 1.722,8.505 1.701,8.375 1.64,8.255 1.541,8.156 1.298,8.077 1.246,8.077 1.116,8.098 0.996,8.159 0.897,8.258 0.818,8.501 0.818,8.941 0.823,8.941 0.843,9.032 0.882,9.117 0.937,9.193 1.007,9.255 1.088,9.302 1.177,9.33 1.27,9.34
  Bottom Layer region: -1.27,9.34 -1.177,9.33 -1.088,9.302 -1.007,9.255 -0.937,9.193 -0.882,9.117 -0.843,9.032 -0.823,8.941 -0.818,8.941 -0.818,8.505 -0.839,8.375 -0.9,8.255 -0.999,8.156 -1.242,8.077 -1.294,8.077 -1.424,8.098 -1.544,8.159 -1.643,8.258 -1.722,8.501 -1.722,8.941 -1.717,8.941 -1.697,9.032 -1.658,9.117 -1.603,9.193 -1.533,9.255 -1.452,9.302 -1.363,9.33 -1.27,9.34
  Bottom Layer region: -3.81,9.34 -3.717,9.33 -3.628,9.302 -3.547,9.255 -3.477,9.193 -3.422,9.117 -3.383,9.032 -3.363,8.941 -3.358,8.941 -3.358,8.505 -3.379,8.375 -3.44,8.255 -3.539,8.156 -3.782,8.077 -3.834,8.077 -3.964,8.098 -4.084,8.159 -4.183,8.258 -4.262,8.501 -4.262,8.941 -4.257,8.941 -4.237,9.032 -4.198,9.117 -4.143,9.193 -4.073,9.255 -3.992,9.302 -3.903,9.33 -3.81,9.34
  Bottom Layer region: -6.35,9.34 -6.257,9.33 -6.168,9.302 -6.087,9.255 -6.017,9.193 -5.962,9.117 -5.923,9.032 -5.903,8.941 -5.898,8.941 -5.898,8.505 -5.919,8.375 -5.98,8.255 -6.079,8.156 -6.322,8.077 -6.374,8.077 -6.504,8.098 -6.624,8.159 -6.723,8.258 -6.802,8.501 -6.802,8.941 -6.797,8.941 -6.777,9.032 -6.738,9.117 -6.683,9.193 -6.613,9.255 -6.532,9.302 -6.443,9.33 -6.35,9.34
  Bottom Layer region: -6.35,-9.34 -6.443,-9.33 -6.532,-9.302 -6.613,-9.255 -6.683,-9.193 -6.738,-9.117 -6.777,-9.032 -6.797,-8.941 -6.802,-8.941 -6.802,-8.505 -6.781,-8.375 -6.72,-8.255 -6.621,-8.156 -6.378,-8.077 -6.326,-8.077 -6.196,-8.098 -6.076,-8.159 -5.977,-8.258 -5.898,-8.501 -5.898,-8.941 -5.903,-8.941 -5.923,-9.032 -5.962,-9.117 -6.017,-9.193 -6.087,-9.255 -6.168,-9.302 -6.257,-9.33 -6.35,-9.34
  Bottom Layer region: -3.81,-9.34 -3.903,-9.33 -3.992,-9.302 -4.073,-9.255 -4.143,-9.193 -4.198,-9.117 -4.237,-9.032 -4.257,-8.941 -4.262,-8.941 -4.262,-8.505 -4.241,-8.375 -4.18,-8.255 -4.081,-8.156 -3.838,-8.077 -3.786,-8.077 -3.656,-8.098 -3.536,-8.159 -3.437,-8.258 -3.358,-8.501 -3.358,-8.941 -3.363,-8.941 -3.383,-9.032 -3.422,-9.117 -3.477,-9.193 -3.547,-9.255 -3.628,-9.302 -3.717,-9.33 -3.81,-9.34
  Bottom Layer region: -1.27,-9.34 -1.363,-9.33 -1.452,-9.302 -1.533,-9.255 -1.603,-9.193 -1.658,-9.117 -1.697,-9.032 -1.717,-8.941 -1.722,-8.941 -1.722,-8.505 -1.701,-8.375 -1.64,-8.255 -1.541,-8.156 -1.298,-8.077 -1.246,-8.077 -1.116,-8.098 -0.996,-8.159 -0.897,-8.258 -0.818,-8.501 -0.818,-8.941 -0.823,-8.941 -0.843,-9.032 -0.882,-9.117 -0.937,-9.193 -1.007,-9.255 -1.088,-9.302 -1.177,-9.33 -1.27,-9.34
  Multi-Layer region: 7.173,8.941 7.193,9.032 7.232,9.117 7.287,9.193 7.357,9.255 7.438,9.302 7.527,9.33 7.62,9.34 7.713,9.33 7.802,9.302 7.883,9.255 7.953,9.193 8.008,9.117 8.047,9.032 8.067,8.941 8.072,8.941 8.072,8.077 7.168,8.077 7.168,8.941 7.173,8.941
  Multi-Layer region: 7.545,7.045 7.439,7.053 7.336,7.078 7.239,7.119 7.148,7.174 7.068,7.243 6.999,7.323 6.944,7.414 6.903,7.511 6.878,7.614 6.87,7.72 6.878,7.826 6.903,7.929 6.944,8.026 6.999,8.117 7.068,8.197 7.148,8.266 7.239,8.321 7.336,8.362 7.439,8.387 7.545,8.395 7.651,8.387 7.754,8.362 7.851,8.321 7.942,8.266 8.022,8.197 8.091,8.117 8.146,8.026 8.187,7.929 8.212,7.826 8.22,7.72 8.212,7.614 8.187,7.511 8.146,7.414 8.091,7.323 8.022,7.243 7.942,7.174 7.851,7.119 7.754,7.078 7.651,7.053 7.545,7.045
  Multi-Layer region: 4.633,8.941 4.653,9.032 4.692,9.117 4.747,9.193 4.817,9.255 4.898,9.302 4.987,9.33 5.08,9.34 5.173,9.33 5.262,9.302 5.343,9.255 5.413,9.193 5.468,9.117 5.507,9.032 5.527,8.941 5.532,8.941 5.532,8.077 4.628,8.077 4.628,8.941 4.633,8.941
  Multi-Layer region: 4.905,6.945 4.799,6.953 4.696,6.978 4.599,7.019 4.508,7.074 4.428,7.143 4.359,7.223 4.304,7.314 4.263,7.411 4.238,7.514 4.23,7.62 4.238,7.726 4.263,7.829 4.304,7.926 4.359,8.017 4.428,8.097 4.508,8.166 4.599,8.221 4.696,8.262 4.799,8.287 4.905,8.295 5.011,8.287 5.114,8.262 5.211,8.221 5.302,8.166 5.382,8.097 5.451,8.017 5.506,7.926 5.547,7.829 5.572,7.726 5.58,7.62 5.572,7.514 5.547,7.411 5.506,7.314 5.451,7.223 5.382,7.143 5.302,7.074 5.211,7.019 5.114,6.978 5.011,6.953 4.905,6.945
  Multi-Layer region: 2.093,8.941 2.113,9.032 2.152,9.117 2.207,9.193 2.277,9.255 2.358,9.302 2.447,9.33 2.54,9.34 2.633,9.33 2.722,9.302 2.803,9.255 2.873,9.193 2.928,9.117 2.967,9.032 2.987,8.941 2.992,8.941 2.992,8.077 2.088,8.077 2.088,8.941 2.093,8.941
  Multi-Layer region: 2.365,6.945 2.259,6.953 2.156,6.978 2.059,7.019 1.968,7.074 1.888,7.143 1.819,7.223 1.764,7.314 1.723,7.411 1.698,7.514 1.69,7.62 1.698,7.726 1.723,7.829 1.764,7.926 1.819,8.017 1.888,8.097 1.968,8.166 2.059,8.221 2.156,8.262 2.259,8.287 2.365,8.295 2.471,8.287 2.574,8.262 2.671,8.221 2.762,8.166 2.842,8.097 2.911,8.017 2.966,7.926 3.007,7.829 3.032,7.726 3.04,7.62 3.032,7.514 3.007,7.411 2.966,7.314 2.911,7.223 2.842,7.143 2.762,7.074 2.671,7.019 2.574,6.978 2.471,6.953 2.365,6.945
  Multi-Layer region: -0.447,8.941 -0.427,9.032 -0.388,9.117 -0.333,9.193 -0.263,9.255 -0.182,9.302 -0.093,9.33 0,9.34 0.093,9.33 0.182,9.302 0.263,9.255 0.333,9.193 0.388,9.117 0.427,9.032 0.447,8.941 0.452,8.941 0.452,8.077 -0.452,8.077 -0.452,8.941 -0.447,8.941
  Multi-Layer region: -0.175,6.945 -0.281,6.953 -0.384,6.978 -0.481,7.019 -0.572,7.074 -0.652,7.143 -0.721,7.223 -0.776,7.314 -0.817,7.411 -0.842,7.514 -0.85,7.62 -0.842,7.726 -0.817,7.829 -0.776,7.926 -0.721,8.017 -0.652,8.097 -0.572,8.166 -0.481,8.221 -0.384,8.262 -0.281,8.287 -0.175,8.295 -0.069,8.287 0.034,8.262 0.131,8.221 0.222,8.166 0.302,8.097 0.371,8.017 0.426,7.926 0.467,7.829 0.492,7.726 0.5,7.62 0.492,7.514 0.467,7.411 0.426,7.314 0.371,7.223 0.302,7.143 0.222,7.074 0.131,7.019 0.034,6.978 -0.069,6.953 -0.175,6.945
  Multi-Layer region: -2.987,8.941 -2.967,9.032 -2.928,9.117 -2.873,9.193 -2.803,9.255 -2.722,9.302 -2.633,9.33 -2.54,9.34 -2.447,9.33 -2.358,9.302 -2.277,9.255 -2.207,9.193 -2.152,9.117 -2.113,9.032 -2.093,8.941 -2.088,8.941 -2.088,8.077 -2.992,8.077 -2.992,8.941 -2.987,8.941
  Multi-Layer region: -2.715,6.945 -2.821,6.953 -2.924,6.978 -3.021,7.019 -3.112,7.074 -3.192,7.143 -3.261,7.223 -3.316,7.314 -3.357,7.411 -3.382,7.514 -3.39,7.62 -3.382,7.726 -3.357,7.829 -3.316,7.926 -3.261,8.017 -3.192,8.097 -3.112,8.166 -3.021,8.221 -2.924,8.262 -2.821,8.287 -2.715,8.295 -2.609,8.287 -2.506,8.262 -2.409,8.221 -2.318,8.166 -2.238,8.097 -2.169,8.017 -2.114,7.926 -2.073,7.829 -2.048,7.726 -2.04,7.62 -2.048,7.514 -2.073,7.411 -2.114,7.314 -2.169,7.223 -2.238,7.143 -2.318,7.074 -2.409,7.019 -2.506,6.978 -2.609,6.953 -2.715,6.945
  Multi-Layer region: -5.527,8.941 -5.507,9.032 -5.468,9.117 -5.413,9.193 -5.343,9.255 -5.262,9.302 -5.173,9.33 -5.08,9.34 -4.987,9.33 -4.898,9.302 -4.817,9.255 -4.747,9.193 -4.692,9.117 -4.653,9.032 -4.633,8.941 -4.628,8.941 -4.628,8.077 -5.532,8.077 -5.532,8.941 -5.527,8.941
  Multi-Layer region: -5.255,6.945 -5.361,6.953 -5.464,6.978 -5.561,7.019 -5.652,7.074 -5.732,7.143 -5.801,7.223 -5.856,7.314 -5.897,7.411 -5.922,7.514 -5.93,7.62 -5.922,7.726 -5.897,7.829 -5.856,7.926 -5.801,8.017 -5.732,8.097 -5.652,8.166 -5.561,8.221 -5.464,8.262 -5.361,8.287 -5.255,8.295 -5.149,8.287 -5.046,8.262 -4.949,8.221 -4.858,8.166 -4.778,8.097 -4.709,8.017 -4.654,7.926 -4.613,7.829 -4.588,7.726 -4.58,7.62 -4.588,7.514 -4.613,7.411 -4.654,7.314 -4.709,7.223 -4.778,7.143 -4.858,7.074 -4.949,7.019 -5.046,6.978 -5.149,6.953 -5.255,6.945
  Multi-Layer region: -8.067,8.941 -8.047,9.032 -8.008,9.117 -7.953,9.193 -7.883,9.255 -7.802,9.302 -7.713,9.33 -7.62,9.34 -7.527,9.33 -7.438,9.302 -7.357,9.255 -7.287,9.193 -7.232,9.117 -7.193,9.032 -7.173,8.941 -7.168,8.941 -7.168,8.077 -8.072,8.077 -8.072,8.941 -8.067,8.941
  Multi-Layer region: -7.695,7.045 -7.801,7.053 -7.904,7.078 -8.001,7.119 -8.092,7.174 -8.172,7.243 -8.241,7.323 -8.296,7.414 -8.337,7.511 -8.362,7.614 -8.37,7.72 -8.362,7.826 -8.337,7.929 -8.296,8.026 -8.241,8.117 -8.172,8.197 -8.092,8.266 -8.001,8.321 -7.904,8.362 -7.801,8.387 -7.695,8.395 -7.589,8.387 -7.486,8.362 -7.389,8.321 -7.298,8.266 -7.218,8.197 -7.149,8.117 -7.094,8.026 -7.053,7.929 -7.028,7.826 -7.02,7.72 -7.028,7.614 -7.053,7.511 -7.094,7.414 -7.149,7.323 -7.218,7.243 -7.298,7.174 -7.389,7.119 -7.486,7.078 -7.589,7.053 -7.695,7.045
  Multi-Layer region: -7.545,-8.395 -7.651,-8.387 -7.754,-8.362 -7.851,-8.321 -7.942,-8.266 -8.022,-8.197 -8.091,-8.117 -8.146,-8.026 -8.187,-7.929 -8.212,-7.826 -8.22,-7.72 -8.212,-7.614 -8.187,-7.511 -8.146,-7.414 -8.091,-7.323 -8.022,-7.243 -7.942,-7.174 -7.851,-7.119 -7.754,-7.078 -7.651,-7.053 -7.545,-7.045 -7.439,-7.053 -7.336,-7.078 -7.239,-7.119 -7.148,-7.174 -7.068,-7.243 -6.999,-7.323 -6.944,-7.414 -6.903,-7.511 -6.878,-7.614 -6.87,-7.72 -6.878,-7.826 -6.903,-7.929 -6.944,-8.026 -6.999,-8.117 -7.068,-8.197 -7.148,-8.266 -7.239,-8.321 -7.336,-8.362 -7.439,-8.387 -7.545,-8.395
  Multi-Layer region: -7.173,-8.941 -7.193,-9.032 -7.232,-9.117 -7.287,-9.193 -7.357,-9.255 -7.438,-9.302 -7.527,-9.33 -7.62,-9.34 -7.713,-9.33 -7.802,-9.302 -7.883,-9.255 -7.953,-9.193 -8.008,-9.117 -8.047,-9.032 -8.067,-8.941 -8.072,-8.941 -8.072,-8.077 -7.168,-8.077 -7.168,-8.941 -7.173,-8.941
  Multi-Layer region: -4.905,-8.295 -5.011,-8.287 -5.114,-8.262 -5.211,-8.221 -5.302,-8.166 -5.382,-8.097 -5.451,-8.017 -5.506,-7.926 -5.547,-7.829 -5.572,-7.726 -5.58,-7.62 -5.572,-7.514 -5.547,-7.411 -5.506,-7.314 -5.451,-7.223 -5.382,-7.143 -5.302,-7.074 -5.211,-7.019 -5.114,-6.978 -5.011,-6.953 -4.905,-6.945 -4.799,-6.953 -4.696,-6.978 -4.599,-7.019 -4.508,-7.074 -4.428,-7.143 -4.359,-7.223 -4.304,-7.314 -4.263,-7.411 -4.238,-7.514 -4.23,-7.62 -4.238,-7.726 -4.263,-7.829 -4.304,-7.926 -4.359,-8.017 -4.428,-8.097 -4.508,-8.166 -4.599,-8.221 -4.696,-8.262 -4.799,-8.287 -4.905,-8.295
  Multi-Layer region: -4.633,-8.941 -4.653,-9.032 -4.692,-9.117 -4.747,-9.193 -4.817,-9.255 -4.898,-9.302 -4.987,-9.33 -5.08,-9.34 -5.173,-9.33 -5.262,-9.302 -5.343,-9.255 -5.413,-9.193 -5.468,-9.117 -5.507,-9.032 -5.527,-8.941 -5.532,-8.941 -5.532,-8.077 -4.628,-8.077 -4.628,-8.941 -4.633,-8.941
  Multi-Layer region: -2.365,-8.295 -2.471,-8.287 -2.574,-8.262 -2.671,-8.221 -2.762,-8.166 -2.842,-8.097 -2.911,-8.017 -2.966,-7.926 -3.007,-7.829 -3.032,-7.726 -3.04,-7.62 -3.032,-7.514 -3.007,-7.411 -2.966,-7.314 -2.911,-7.223 -2.842,-7.143 -2.762,-7.074 -2.671,-7.019 -2.574,-6.978 -2.471,-6.953 -2.365,-6.945 -2.259,-6.953 -2.156,-6.978 -2.059,-7.019 -1.968,-7.074 -1.888,-7.143 -1.819,-7.223 -1.764,-7.314 -1.723,-7.411 -1.698,-7.514 -1.69,-7.62 -1.698,-7.726 -1.723,-7.829 -1.764,-7.926 -1.819,-8.017 -1.888,-8.097 -1.968,-8.166 -2.059,-8.221 -2.156,-8.262 -2.259,-8.287 -2.365,-8.295
  Multi-Layer region: -2.093,-8.941 -2.113,-9.032 -2.152,-9.117 -2.207,-9.193 -2.277,-9.255 -2.358,-9.302 -2.447,-9.33 -2.54,-9.34 -2.633,-9.33 -2.722,-9.302 -2.803,-9.255 -2.873,-9.193 -2.928,-9.117 -2.967,-9.032 -2.987,-8.941 -2.992,-8.941 -2.992,-8.077 -2.088,-8.077 -2.088,-8.941 -2.093,-8.941
  Multi-Layer region: 0.175,-8.295 0.069,-8.287 -0.034,-8.262 -0.131,-8.221 -0.222,-8.166 -0.302,-8.097 -0.371,-8.017 -0.426,-7.926 -0.467,-7.829 -0.492,-7.726 -0.5,-7.62 -0.492,-7.514 -0.467,-7.411 -0.426,-7.314 -0.371,-7.223 -0.302,-7.143 -0.222,-7.074 -0.131,-7.019 -0.034,-6.978 0.069,-6.953 0.175,-6.945 0.281,-6.953 0.384,-6.978 0.481,-7.019 0.572,-7.074 0.652,-7.143 0.721,-7.223 0.776,-7.314 0.817,-7.411 0.842,-7.514 0.85,-7.62 0.842,-7.726 0.817,-7.829 0.776,-7.926 0.721,-8.017 0.652,-8.097 0.572,-8.166 0.481,-8.221 0.384,-8.262 0.281,-8.287 0.175,-8.295
  Multi-Layer region: 0.447,-8.941 0.427,-9.032 0.388,-9.117 0.333,-9.193 0.263,-9.255 0.182,-9.302 0.093,-9.33 0,-9.34 -0.093,-9.33 -0.182,-9.302 -0.263,-9.255 -0.333,-9.193 -0.388,-9.117 -0.427,-9.032 -0.447,-8.941 -0.452,-8.941 -0.452,-8.077 0.452,-8.077 0.452,-8.941 0.447,-8.941
  Multi-Layer region: 2.715,-8.295 2.609,-8.287 2.506,-8.262 2.409,-8.221 2.318,-8.166 2.238,-8.097 2.169,-8.017 2.114,-7.926 2.073,-7.829 2.048,-7.726 2.04,-7.62 2.048,-7.514 2.073,-7.411 2.114,-7.314 2.169,-7.223 2.238,-7.143 2.318,-7.074 2.409,-7.019 2.506,-6.978 2.609,-6.953 2.715,-6.945 2.821,-6.953 2.924,-6.978 3.021,-7.019 3.112,-7.074 3.192,-7.143 3.261,-7.223 3.316,-7.314 3.357,-7.411 3.382,-7.514 3.39,-7.62 3.382,-7.726 3.357,-7.829 3.316,-7.926 3.261,-8.017 3.192,-8.097 3.112,-8.166 3.021,-8.221 2.924,-8.262 2.821,-8.287 2.715,-8.295
  Multi-Layer region: 2.987,-8.941 2.967,-9.032 2.928,-9.117 2.873,-9.193 2.803,-9.255 2.722,-9.302 2.633,-9.33 2.54,-9.34 2.447,-9.33 2.358,-9.302 2.277,-9.255 2.207,-9.193 2.152,-9.117 2.113,-9.032 2.093,-8.941 2.088,-8.941 2.088,-8.077 2.992,-8.077 2.992,-8.941 2.987,-8.941
  Multi-Layer region: 5.255,-8.295 5.149,-8.287 5.046,-8.262 4.949,-8.221 4.858,-8.166 4.778,-8.097 4.709,-8.017 4.654,-7.926 4.613,-7.829 4.588,-7.726 4.58,-7.62 4.588,-7.514 4.613,-7.411 4.654,-7.314 4.709,-7.223 4.778,-7.143 4.858,-7.074 4.949,-7.019 5.046,-6.978 5.149,-6.953 5.255,-6.945 5.361,-6.953 5.464,-6.978 5.561,-7.019 5.652,-7.074 5.732,-7.143 5.801,-7.223 5.856,-7.314 5.897,-7.411 5.922,-7.514 5.93,-7.62 5.922,-7.726 5.897,-7.829 5.856,-7.926 5.801,-8.017 5.732,-8.097 5.652,-8.166 5.561,-8.221 5.464,-8.262 5.361,-8.287 5.255,-8.295
  Multi-Layer region: 5.527,-8.941 5.507,-9.032 5.468,-9.117 5.413,-9.193 5.343,-9.255 5.262,-9.302 5.173,-9.33 5.08,-9.34 4.987,-9.33 4.898,-9.302 4.817,-9.255 4.747,-9.193 4.692,-9.117 4.653,-9.032 4.633,-8.941 4.628,-8.941 4.628,-8.077 5.532,-8.077 5.532,-8.941 5.527,-8.941
  Multi-Layer region: 7.695,-8.395 7.589,-8.387 7.486,-8.362 7.389,-8.321 7.298,-8.266 7.218,-8.197 7.149,-8.117 7.094,-8.026 7.053,-7.929 7.028,-7.826 7.02,-7.72 7.028,-7.614 7.053,-7.511 7.094,-7.414 7.149,-7.323 7.218,-7.243 7.298,-7.174 7.389,-7.119 7.486,-7.078 7.589,-7.053 7.695,-7.045 7.801,-7.053 7.904,-7.078 8.001,-7.119 8.092,-7.174 8.172,-7.243 8.241,-7.323 8.296,-7.414 8.337,-7.511 8.362,-7.614 8.37,-7.72 8.362,-7.826 8.337,-7.929 8.296,-8.026 8.241,-8.117 8.172,-8.197 8.092,-8.266 8.001,-8.321 7.904,-8.362 7.801,-8.387 7.695,-8.395
  Multi-Layer region: 8.067,-8.941 8.047,-9.032 8.008,-9.117 7.953,-9.193 7.883,-9.255 7.802,-9.302 7.713,-9.33 7.62,-9.34 7.527,-9.33 7.438,-9.302 7.357,-9.255 7.287,-9.193 7.232,-9.117 7.193,-9.032 7.173,-8.941 7.168,-8.941 7.168,-8.077 8.072,-8.077 8.072,-8.941 8.067,-8.941
  Multi-Layer region: 6.35,9.34 6.443,9.33 6.532,9.302 6.613,9.255 6.683,9.193 6.738,9.117 6.777,9.032 6.797,8.941 6.802,8.941 6.802,8.505 6.781,8.375 6.72,8.255 6.621,8.156 6.378,8.077 6.326,8.077 6.196,8.098 6.076,8.159 5.977,8.258 5.898,8.501 5.898,8.941 5.903,8.941 5.923,9.032 5.962,9.117 6.017,9.193 6.087,9.255 6.168,9.302 6.257,9.33 6.35,9.34
  Multi-Layer region: 3.81,9.34 3.903,9.33 3.992,9.302 4.073,9.255 4.143,9.193 4.198,9.117 4.237,9.032 4.257,8.941 4.262,8.941 4.262,8.505 4.241,8.375 4.18,8.255 4.081,8.156 3.838,8.077 3.786,8.077 3.656,8.098 3.536,8.159 3.437,8.258 3.358,8.501 3.358,8.941 3.363,8.941 3.383,9.032 3.422,9.117 3.477,9.193 3.547,9.255 3.628,9.302 3.717,9.33 3.81,9.34
  Multi-Layer region: 1.27,9.34 1.363,9.33 1.452,9.302 1.533,9.255 1.603,9.193 1.658,9.117 1.697,9.032 1.717,8.941 1.722,8.941 1.722,8.505 1.701,8.375 1.64,8.255 1.541,8.156 1.298,8.077 1.246,8.077 1.116,8.098 0.996,8.159 0.897,8.258 0.818,8.501 0.818,8.941 0.823,8.941 0.843,9.032 0.882,9.117 0.937,9.193 1.007,9.255 1.088,9.302 1.177,9.33 1.27,9.34
  Multi-Layer region: -1.27,9.34 -1.177,9.33 -1.088,9.302 -1.007,9.255 -0.937,9.193 -0.882,9.117 -0.843,9.032 -0.823,8.941 -0.818,8.941 -0.818,8.505 -0.839,8.375 -0.9,8.255 -0.999,8.156 -1.242,8.077 -1.294,8.077 -1.424,8.098 -1.544,8.159 -1.643,8.258 -1.722,8.501 -1.722,8.941 -1.717,8.941 -1.697,9.032 -1.658,9.117 -1.603,9.193 -1.533,9.255 -1.452,9.302 -1.363,9.33 -1.27,9.34
  Multi-Layer region: -3.81,9.34 -3.717,9.33 -3.628,9.302 -3.547,9.255 -3.477,9.193 -3.422,9.117 -3.383,9.032 -3.363,8.941 -3.358,8.941 -3.358,8.505 -3.379,8.375 -3.44,8.255 -3.539,8.156 -3.782,8.077 -3.834,8.077 -3.964,8.098 -4.084,8.159 -4.183,8.258 -4.262,8.501 -4.262,8.941 -4.257,8.941 -4.237,9.032 -4.198,9.117 -4.143,9.193 -4.073,9.255 -3.992,9.302 -3.903,9.33 -3.81,9.34
  Multi-Layer region: -6.35,9.34 -6.257,9.33 -6.168,9.302 -6.087,9.255 -6.017,9.193 -5.962,9.117 -5.923,9.032 -5.903,8.941 -5.898,8.941 -5.898,8.505 -5.919,8.375 -5.98,8.255 -6.079,8.156 -6.322,8.077 -6.374,8.077 -6.504,8.098 -6.624,8.159 -6.723,8.258 -6.802,8.501 -6.802,8.941 -6.797,8.941 -6.777,9.032 -6.738,9.117 -6.683,9.193 -6.613,9.255 -6.532,9.302 -6.443,9.33 -6.35,9.34
  Multi-Layer region: -6.35,-9.34 -6.443,-9.33 -6.532,-9.302 -6.613,-9.255 -6.683,-9.193 -6.738,-9.117 -6.777,-9.032 -6.797,-8.941 -6.802,-8.941 -6.802,-8.505 -6.781,-8.375 -6.72,-8.255 -6.621,-8.156 -6.378,-8.077 -6.326,-8.077 -6.196,-8.098 -6.076,-8.159 -5.977,-8.258 -5.898,-8.501 -5.898,-8.941 -5.903,-8.941 -5.923,-9.032 -5.962,-9.117 -6.017,-9.193 -6.087,-9.255 -6.168,-9.302 -6.257,-9.33 -6.35,-9.34
  Multi-Layer region: -3.81,-9.34 -3.903,-9.33 -3.992,-9.302 -4.073,-9.255 -4.143,-9.193 -4.198,-9.117 -4.237,-9.032 -4.257,-8.941 -4.262,-8.941 -4.262,-8.505 -4.241,-8.375 -4.18,-8.255 -4.081,-8.156 -3.838,-8.077 -3.786,-8.077 -3.656,-8.098 -3.536,-8.159 -3.437,-8.258 -3.358,-8.501 -3.358,-8.941 -3.363,-8.941 -3.383,-9.032 -3.422,-9.117 -3.477,-9.193 -3.547,-9.255 -3.628,-9.302 -3.717,-9.33 -3.81,-9.34
  Multi-Layer region: -1.27,-9.34 -1.363,-9.33 -1.452,-9.302 -1.533,-9.255 -1.603,-9.193 -1.658,-9.117 -1.697,-9.032 -1.717,-8.941 -1.722,-8.941 -1.722,-8.505 -1.701,-8.375 -1.64,-8.255 -1.541,-8.156 -1.298,-8.077 -1.246,-8.077 -1.116,-8.098 -0.996,-8.159 -0.897,-8.258 -0.818,-8.501 -0.818,-8.941 -0.823,-8.941 -0.843,-9.032 -0.882,-9.117 -0.937,-9.193 -1.007,-9.255 -1.088,-9.302 -1.177,-9.33 -1.27,-9.34
  silkscreen extent -10.47,-8.89 10.48,8.89
CONN-SMD_2P-P1.50_ZX-ZH1.5-2PWT [mm]
  rect 1x2.3 smd paste+0 mask+0.05: 1(-0.75,2) 2(0.75,2)
  rect 1x2.5 smd paste+0 mask+0.05: 3(2.75,-2) 4(-2.75,-2)
  silkscreen extent -3.27,-3.97 3.27,3.04
FPC-SMD_4P-P0.50_05A20L4P [mm]
  rect 0.3x1.25 smd paste+0 mask+0.05: 1(-0.75,1.162) 2(-0.25,1.162) 3(0.25,1.162) 4(0.75,1.162)
  rect 2x3 smd paste+0 mask+0.05: 5(2.29,-1.162) 6(-2.29,-1.162)
  silkscreen extent -3.2,-4.6 3.2,1.8
SW_MJTP1230G [mm]
  round 1.508 hole 1 paste+0 mask+0.102: 11(-3.25,2.25) 12(3.25,2.25) 21(-3.25,-2.25) 22(3.25,-2.25)
  silkscreen extent -3,-3 3,3
TC2030-CTX-NL [mil]
  round 30.98 smd paste+0 mask+4: 1(-25,50) 2(25,50) 3(-25,0) 4(25,0) 5(-25,-50) 6(25,-50)
  round 39.02 hole 39.02 unplated paste+0 mask+4: ""(-40,-100) ""(0,100) ""(40,-100)
  silkscreen extent -60,-50 60,100

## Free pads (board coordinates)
  round 157.48 hole 125.98: 1(3335.35,3437.01) 1(3335.35,4559.06) 1(4532.2,3437.01) 1(4532.2,4559.06)
  round 236.22 hole 236.22 unplated: 1(3654.25,3358.27)
  round 125.98 hole 125.98 unplated: 1(3933.78,3275.59)

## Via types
v1: diameter 24.02, hole 12, Top Layer to Bottom Layer, 11 vias

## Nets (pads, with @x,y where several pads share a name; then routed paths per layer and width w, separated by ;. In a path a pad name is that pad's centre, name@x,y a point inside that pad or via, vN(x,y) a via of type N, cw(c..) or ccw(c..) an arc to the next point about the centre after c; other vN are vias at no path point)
3V3: J1.1 SWD.1 | length 974.5
  Top Layer w11.81: J1.1@4171.18,3412.01 4181.02,3421.85 v1(4181.02,3427.17)
  Bottom Layer w11.81: v1(4181.02,3427.17) 4058.66,3549.53 3904.98,3549.53 3875.83,3578.68 3875.83,3641.13 3898.36,3663.66 3930.22,3663.66 3934.16,3667.6 3946.34,3667.6 SWD.1@4259.84,3981.1
3V3_OUT: U1.2 U7.12 | length 1287.8
  Top Layer w10: v1(3388.5,3985.14) 3447.46,4044.09 3931.65,4044.09 3985.79,3989.96 3985.79,3954.51 4008.37,3931.93 4096.36,3931.93 v1(4096.36,3935.14)
  Bottom Layer w10: U1.2@3388.5,3935.53 v1(3388.5,3985.14) ; v1(4096.36,3935.14) 4096.36,4015.14 4317.24,4236.02 4317.24,4279.13
BAT_IN: SW1.1 U3.2 | length 726.6
  Bottom Layer w11.81: U3.2@3624.73,3948.82 3624.73,4257.88 3849.14,4482.29 3896.38,4482.29 SW1.1@3933.78,4519.69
